VERSION 5.8 ;
BUSBITCHARS "[]" ;
DIVIDERCHAR "/" ;
UNITS
    DATABASE MICRONS 1000 ;
END UNITS

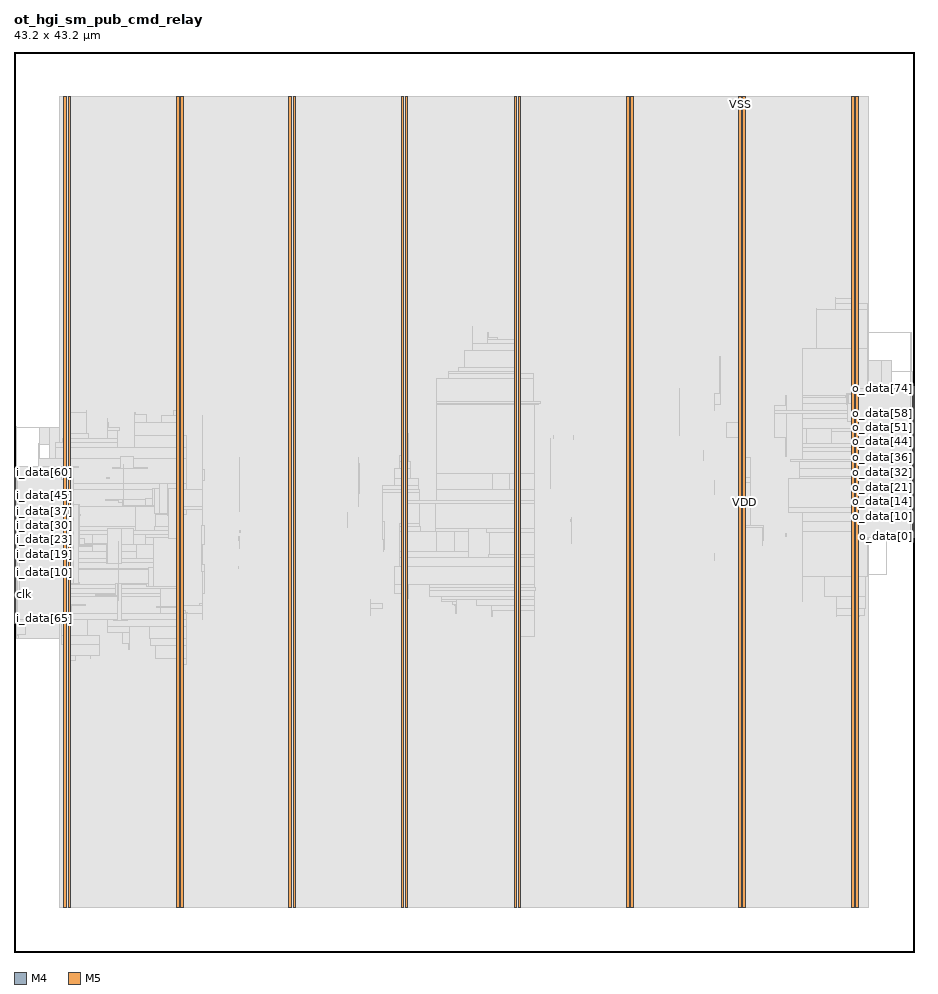
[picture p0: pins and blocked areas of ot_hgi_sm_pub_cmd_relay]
MACRO ot_hgi_sm_pub_cmd_relay
  FOREIGN ot_hgi_sm_pub_cmd_relay 0 0 ;
  CLASS BLOCK ;
  SIZE 43.2 BY 43.2 ;
  PIN clk
    DIRECTION INPUT ;
    USE SIGNAL ;
    PORT
      LAYER M4 ;
        RECT  0 17.136 0.084 17.16 ;
    END
  END clk
  PIN i_data[0]
    DIRECTION INPUT ;
    USE SIGNAL ;
    PORT
      LAYER M4 ;
        RECT  0 17.232 0.084 17.256 ;
    END
  END i_data[0]
  PIN i_data[10]
    DIRECTION INPUT ;
    USE SIGNAL ;
    PORT
      LAYER M4 ;
        RECT  0 18.192 0.084 18.216 ;
    END
  END i_data[10]
  PIN i_data[11]
    DIRECTION INPUT ;
    USE SIGNAL ;
    PORT
      LAYER M4 ;
        RECT  0 18.288 0.084 18.312 ;
    END
  END i_data[11]
  PIN i_data[12]
    DIRECTION INPUT ;
    USE SIGNAL ;
    PORT
      LAYER M4 ;
        RECT  0 18.384 0.084 18.408 ;
    END
  END i_data[12]
  PIN i_data[13]
    DIRECTION INPUT ;
    USE SIGNAL ;
    PORT
      LAYER M4 ;
        RECT  0 18.48 0.084 18.504 ;
    END
  END i_data[13]
  PIN i_data[14]
    DIRECTION INPUT ;
    USE SIGNAL ;
    PORT
      LAYER M4 ;
        RECT  0 18.576 0.084 18.6 ;
    END
  END i_data[14]
  PIN i_data[15]
    DIRECTION INPUT ;
    USE SIGNAL ;
    PORT
      LAYER M4 ;
        RECT  0 18.672 0.084 18.696 ;
    END
  END i_data[15]
  PIN i_data[16]
    DIRECTION INPUT ;
    USE SIGNAL ;
    PORT
      LAYER M4 ;
        RECT  0 18.768 0.084 18.792 ;
    END
  END i_data[16]
  PIN i_data[17]
    DIRECTION INPUT ;
    USE SIGNAL ;
    PORT
      LAYER M4 ;
        RECT  0 18.864 0.084 18.888 ;
    END
  END i_data[17]
  PIN i_data[18]
    DIRECTION INPUT ;
    USE SIGNAL ;
    PORT
      LAYER M4 ;
        RECT  0 18.96 0.084 18.984 ;
    END
  END i_data[18]
  PIN i_data[19]
    DIRECTION INPUT ;
    USE SIGNAL ;
    PORT
      LAYER M4 ;
        RECT  0 19.056 0.084 19.08 ;
    END
  END i_data[19]
  PIN i_data[1]
    DIRECTION INPUT ;
    USE SIGNAL ;
    PORT
      LAYER M4 ;
        RECT  0 17.328 0.084 17.352 ;
    END
  END i_data[1]
  PIN i_data[20]
    DIRECTION INPUT ;
    USE SIGNAL ;
    PORT
      LAYER M4 ;
        RECT  0 19.152 0.084 19.176 ;
    END
  END i_data[20]
  PIN i_data[21]
    DIRECTION INPUT ;
    USE SIGNAL ;
    PORT
      LAYER M4 ;
        RECT  0 19.248 0.084 19.272 ;
    END
  END i_data[21]
  PIN i_data[22]
    DIRECTION INPUT ;
    USE SIGNAL ;
    PORT
      LAYER M4 ;
        RECT  0 19.344 0.084 19.368 ;
    END
  END i_data[22]
  PIN i_data[23]
    DIRECTION INPUT ;
    USE SIGNAL ;
    PORT
      LAYER M4 ;
        RECT  0 19.44 0.084 19.464 ;
    END
  END i_data[23]
  PIN i_data[24]
    DIRECTION INPUT ;
    USE SIGNAL ;
    PORT
      LAYER M4 ;
        RECT  0 19.536 0.084 19.56 ;
    END
  END i_data[24]
  PIN i_data[25]
    DIRECTION INPUT ;
    USE SIGNAL ;
    PORT
      LAYER M4 ;
        RECT  0 19.632 0.084 19.656 ;
    END
  END i_data[25]
  PIN i_data[26]
    DIRECTION INPUT ;
    USE SIGNAL ;
    PORT
      LAYER M4 ;
        RECT  0 19.728 0.084 19.752 ;
    END
  END i_data[26]
  PIN i_data[27]
    DIRECTION INPUT ;
    USE SIGNAL ;
    PORT
      LAYER M4 ;
        RECT  0 19.824 0.084 19.848 ;
    END
  END i_data[27]
  PIN i_data[28]
    DIRECTION INPUT ;
    USE SIGNAL ;
    PORT
      LAYER M4 ;
        RECT  0 19.92 0.084 19.944 ;
    END
  END i_data[28]
  PIN i_data[29]
    DIRECTION INPUT ;
    USE SIGNAL ;
    PORT
      LAYER M4 ;
        RECT  0 20.016 0.084 20.04 ;
    END
  END i_data[29]
  PIN i_data[2]
    DIRECTION INPUT ;
    USE SIGNAL ;
    PORT
      LAYER M4 ;
        RECT  0 17.424 0.084 17.448 ;
    END
  END i_data[2]
  PIN i_data[30]
    DIRECTION INPUT ;
    USE SIGNAL ;
    PORT
      LAYER M4 ;
        RECT  0 20.112 0.084 20.136 ;
    END
  END i_data[30]
  PIN i_data[31]
    DIRECTION INPUT ;
    USE SIGNAL ;
    PORT
      LAYER M4 ;
        RECT  0 20.208 0.084 20.232 ;
    END
  END i_data[31]
  PIN i_data[32]
    DIRECTION INPUT ;
    USE SIGNAL ;
    PORT
      LAYER M4 ;
        RECT  0 20.304 0.084 20.328 ;
    END
  END i_data[32]
  PIN i_data[33]
    DIRECTION INPUT ;
    USE SIGNAL ;
    PORT
      LAYER M4 ;
        RECT  0 20.4 0.084 20.424 ;
    END
  END i_data[33]
  PIN i_data[34]
    DIRECTION INPUT ;
    USE SIGNAL ;
    PORT
      LAYER M4 ;
        RECT  0 20.496 0.084 20.52 ;
    END
  END i_data[34]
  PIN i_data[35]
    DIRECTION INPUT ;
    USE SIGNAL ;
    PORT
      LAYER M4 ;
        RECT  0 20.592 0.084 20.616 ;
    END
  END i_data[35]
  PIN i_data[36]
    DIRECTION INPUT ;
    USE SIGNAL ;
    PORT
      LAYER M4 ;
        RECT  0 20.688 0.084 20.712 ;
    END
  END i_data[36]
  PIN i_data[37]
    DIRECTION INPUT ;
    USE SIGNAL ;
    PORT
      LAYER M4 ;
        RECT  0 20.784 0.084 20.808 ;
    END
  END i_data[37]
  PIN i_data[38]
    DIRECTION INPUT ;
    USE SIGNAL ;
    PORT
      LAYER M4 ;
        RECT  0 20.88 0.084 20.904 ;
    END
  END i_data[38]
  PIN i_data[39]
    DIRECTION INPUT ;
    USE SIGNAL ;
    PORT
      LAYER M4 ;
        RECT  0 20.976 0.084 21 ;
    END
  END i_data[39]
  PIN i_data[3]
    DIRECTION INPUT ;
    USE SIGNAL ;
    PORT
      LAYER M4 ;
        RECT  0 17.52 0.084 17.544 ;
    END
  END i_data[3]
  PIN i_data[40]
    DIRECTION INPUT ;
    USE SIGNAL ;
    PORT
      LAYER M4 ;
        RECT  0 21.072 0.084 21.096 ;
    END
  END i_data[40]
  PIN i_data[41]
    DIRECTION INPUT ;
    USE SIGNAL ;
    PORT
      LAYER M4 ;
        RECT  0 21.168 0.084 21.192 ;
    END
  END i_data[41]
  PIN i_data[42]
    DIRECTION INPUT ;
    USE SIGNAL ;
    PORT
      LAYER M4 ;
        RECT  0 21.264 0.084 21.288 ;
    END
  END i_data[42]
  PIN i_data[43]
    DIRECTION INPUT ;
    USE SIGNAL ;
    PORT
      LAYER M4 ;
        RECT  0 21.36 0.084 21.384 ;
    END
  END i_data[43]
  PIN i_data[44]
    DIRECTION INPUT ;
    USE SIGNAL ;
    PORT
      LAYER M4 ;
        RECT  0 21.456 0.084 21.48 ;
    END
  END i_data[44]
  PIN i_data[45]
    DIRECTION INPUT ;
    USE SIGNAL ;
    PORT
      LAYER M4 ;
        RECT  0 21.552 0.084 21.576 ;
    END
  END i_data[45]
  PIN i_data[46]
    DIRECTION INPUT ;
    USE SIGNAL ;
    PORT
      LAYER M4 ;
        RECT  0 21.648 0.084 21.672 ;
    END
  END i_data[46]
  PIN i_data[47]
    DIRECTION INPUT ;
    USE SIGNAL ;
    PORT
      LAYER M4 ;
        RECT  0 21.744 0.084 21.768 ;
    END
  END i_data[47]
  PIN i_data[48]
    DIRECTION INPUT ;
    USE SIGNAL ;
    PORT
      LAYER M4 ;
        RECT  0 21.84 0.084 21.864 ;
    END
  END i_data[48]
  PIN i_data[49]
    DIRECTION INPUT ;
    USE SIGNAL ;
    PORT
      LAYER M4 ;
        RECT  0 21.936 0.084 21.96 ;
    END
  END i_data[49]
  PIN i_data[4]
    DIRECTION INPUT ;
    USE SIGNAL ;
    PORT
      LAYER M4 ;
        RECT  0 17.616 0.084 17.64 ;
    END
  END i_data[4]
  PIN i_data[50]
    DIRECTION INPUT ;
    USE SIGNAL ;
    PORT
      LAYER M4 ;
        RECT  0 22.032 0.084 22.056 ;
    END
  END i_data[50]
  PIN i_data[51]
    DIRECTION INPUT ;
    USE SIGNAL ;
    PORT
      LAYER M4 ;
        RECT  0 22.128 0.084 22.152 ;
    END
  END i_data[51]
  PIN i_data[52]
    DIRECTION INPUT ;
    USE SIGNAL ;
    PORT
      LAYER M4 ;
        RECT  0 22.224 0.084 22.248 ;
    END
  END i_data[52]
  PIN i_data[53]
    DIRECTION INPUT ;
    USE SIGNAL ;
    PORT
      LAYER M4 ;
        RECT  0 22.32 0.084 22.344 ;
    END
  END i_data[53]
  PIN i_data[54]
    DIRECTION INPUT ;
    USE SIGNAL ;
    PORT
      LAYER M4 ;
        RECT  0 22.416 0.084 22.44 ;
    END
  END i_data[54]
  PIN i_data[55]
    DIRECTION INPUT ;
    USE SIGNAL ;
    PORT
      LAYER M4 ;
        RECT  0 22.512 0.084 22.536 ;
    END
  END i_data[55]
  PIN i_data[56]
    DIRECTION INPUT ;
    USE SIGNAL ;
    PORT
      LAYER M4 ;
        RECT  0 22.608 0.084 22.632 ;
    END
  END i_data[56]
  PIN i_data[57]
    DIRECTION INPUT ;
    USE SIGNAL ;
    PORT
      LAYER M4 ;
        RECT  0 22.704 0.084 22.728 ;
    END
  END i_data[57]
  PIN i_data[58]
    DIRECTION INPUT ;
    USE SIGNAL ;
    PORT
      LAYER M4 ;
        RECT  0 22.8 0.084 22.824 ;
    END
  END i_data[58]
  PIN i_data[59]
    DIRECTION INPUT ;
    USE SIGNAL ;
    PORT
      LAYER M4 ;
        RECT  0 22.896 0.084 22.92 ;
    END
  END i_data[59]
  PIN i_data[5]
    DIRECTION INPUT ;
    USE SIGNAL ;
    PORT
      LAYER M4 ;
        RECT  0 17.712 0.084 17.736 ;
    END
  END i_data[5]
  PIN i_data[60]
    DIRECTION INPUT ;
    USE SIGNAL ;
    PORT
      LAYER M4 ;
        RECT  0 22.992 0.084 23.016 ;
    END
  END i_data[60]
  PIN i_data[61]
    DIRECTION INPUT ;
    USE SIGNAL ;
    PORT
      LAYER M4 ;
        RECT  0 23.088 0.084 23.112 ;
    END
  END i_data[61]
  PIN i_data[62]
    DIRECTION INPUT ;
    USE SIGNAL ;
    PORT
      LAYER M4 ;
        RECT  0 23.184 0.084 23.208 ;
    END
  END i_data[62]
  PIN i_data[63]
    DIRECTION INPUT ;
    USE SIGNAL ;
    PORT
      LAYER M4 ;
        RECT  0 15.792 0.084 15.816 ;
    END
  END i_data[63]
  PIN i_data[64]
    DIRECTION INPUT ;
    USE SIGNAL ;
    PORT
      LAYER M4 ;
        RECT  0 15.888 0.084 15.912 ;
    END
  END i_data[64]
  PIN i_data[65]
    DIRECTION INPUT ;
    USE SIGNAL ;
    PORT
      LAYER M4 ;
        RECT  0 15.984 0.084 16.008 ;
    END
  END i_data[65]
  PIN i_data[66]
    DIRECTION INPUT ;
    USE SIGNAL ;
    PORT
      LAYER M4 ;
        RECT  0 16.08 0.084 16.104 ;
    END
  END i_data[66]
  PIN i_data[67]
    DIRECTION INPUT ;
    USE SIGNAL ;
    PORT
      LAYER M4 ;
        RECT  0 16.176 0.084 16.2 ;
    END
  END i_data[67]
  PIN i_data[68]
    DIRECTION INPUT ;
    USE SIGNAL ;
    PORT
      LAYER M4 ;
        RECT  0 16.272 0.084 16.296 ;
    END
  END i_data[68]
  PIN i_data[69]
    DIRECTION INPUT ;
    USE SIGNAL ;
    PORT
      LAYER M4 ;
        RECT  0 16.368 0.084 16.392 ;
    END
  END i_data[69]
  PIN i_data[6]
    DIRECTION INPUT ;
    USE SIGNAL ;
    PORT
      LAYER M4 ;
        RECT  0 17.808 0.084 17.832 ;
    END
  END i_data[6]
  PIN i_data[70]
    DIRECTION INPUT ;
    USE SIGNAL ;
    PORT
      LAYER M4 ;
        RECT  0 16.464 0.084 16.488 ;
    END
  END i_data[70]
  PIN i_data[71]
    DIRECTION INPUT ;
    USE SIGNAL ;
    PORT
      LAYER M4 ;
        RECT  0 16.56 0.084 16.584 ;
    END
  END i_data[71]
  PIN i_data[72]
    DIRECTION INPUT ;
    USE SIGNAL ;
    PORT
      LAYER M4 ;
        RECT  0 16.656 0.084 16.68 ;
    END
  END i_data[72]
  PIN i_data[73]
    DIRECTION INPUT ;
    USE SIGNAL ;
    PORT
      LAYER M4 ;
        RECT  0 16.752 0.084 16.776 ;
    END
  END i_data[73]
  PIN i_data[74]
    DIRECTION INPUT ;
    USE SIGNAL ;
    PORT
      LAYER M4 ;
        RECT  0 16.848 0.084 16.872 ;
    END
  END i_data[74]
  PIN i_data[7]
    DIRECTION INPUT ;
    USE SIGNAL ;
    PORT
      LAYER M4 ;
        RECT  0 17.904 0.084 17.928 ;
    END
  END i_data[7]
  PIN i_data[8]
    DIRECTION INPUT ;
    USE SIGNAL ;
    PORT
      LAYER M4 ;
        RECT  0 18 0.084 18.024 ;
    END
  END i_data[8]
  PIN i_data[9]
    DIRECTION INPUT ;
    USE SIGNAL ;
    PORT
      LAYER M4 ;
        RECT  0 18.096 0.084 18.12 ;
    END
  END i_data[9]
  PIN i_go
    DIRECTION INPUT ;
    USE SIGNAL ;
    PORT
      LAYER M4 ;
        RECT  0 16.944 0.084 16.968 ;
    END
  END i_go
  PIN o_data[0]
    DIRECTION OUTPUT ;
    USE SIGNAL ;
    PORT
      LAYER M4 ;
        RECT  43.116 19.92 43.2 19.944 ;
    END
  END o_data[0]
  PIN o_data[10]
    DIRECTION OUTPUT ;
    USE SIGNAL ;
    PORT
      LAYER M4 ;
        RECT  43.116 20.88 43.2 20.904 ;
    END
  END o_data[10]
  PIN o_data[11]
    DIRECTION OUTPUT ;
    USE SIGNAL ;
    PORT
      LAYER M4 ;
        RECT  43.116 20.976 43.2 21 ;
    END
  END o_data[11]
  PIN o_data[12]
    DIRECTION OUTPUT ;
    USE SIGNAL ;
    PORT
      LAYER M4 ;
        RECT  43.116 21.072 43.2 21.096 ;
    END
  END o_data[12]
  PIN o_data[13]
    DIRECTION OUTPUT ;
    USE SIGNAL ;
    PORT
      LAYER M4 ;
        RECT  43.116 21.168 43.2 21.192 ;
    END
  END o_data[13]
  PIN o_data[14]
    DIRECTION OUTPUT ;
    USE SIGNAL ;
    PORT
      LAYER M4 ;
        RECT  43.116 21.264 43.2 21.288 ;
    END
  END o_data[14]
  PIN o_data[15]
    DIRECTION OUTPUT ;
    USE SIGNAL ;
    PORT
      LAYER M4 ;
        RECT  43.116 21.36 43.2 21.384 ;
    END
  END o_data[15]
  PIN o_data[16]
    DIRECTION OUTPUT ;
    USE SIGNAL ;
    PORT
      LAYER M4 ;
        RECT  43.116 21.456 43.2 21.48 ;
    END
  END o_data[16]
  PIN o_data[17]
    DIRECTION OUTPUT ;
    USE SIGNAL ;
    PORT
      LAYER M4 ;
        RECT  43.116 21.552 43.2 21.576 ;
    END
  END o_data[17]
  PIN o_data[18]
    DIRECTION OUTPUT ;
    USE SIGNAL ;
    PORT
      LAYER M4 ;
        RECT  43.116 21.648 43.2 21.672 ;
    END
  END o_data[18]
  PIN o_data[19]
    DIRECTION OUTPUT ;
    USE SIGNAL ;
    PORT
      LAYER M4 ;
        RECT  43.116 21.744 43.2 21.768 ;
    END
  END o_data[19]
  PIN o_data[1]
    DIRECTION OUTPUT ;
    USE SIGNAL ;
    PORT
      LAYER M4 ;
        RECT  43.116 20.016 43.2 20.04 ;
    END
  END o_data[1]
  PIN o_data[20]
    DIRECTION OUTPUT ;
    USE SIGNAL ;
    PORT
      LAYER M4 ;
        RECT  43.116 21.84 43.2 21.864 ;
    END
  END o_data[20]
  PIN o_data[21]
    DIRECTION OUTPUT ;
    USE SIGNAL ;
    PORT
      LAYER M4 ;
        RECT  43.116 21.936 43.2 21.96 ;
    END
  END o_data[21]
  PIN o_data[22]
    DIRECTION OUTPUT ;
    USE SIGNAL ;
    PORT
      LAYER M4 ;
        RECT  43.116 22.032 43.2 22.056 ;
    END
  END o_data[22]
  PIN o_data[23]
    DIRECTION OUTPUT ;
    USE SIGNAL ;
    PORT
      LAYER M4 ;
        RECT  43.116 22.128 43.2 22.152 ;
    END
  END o_data[23]
  PIN o_data[24]
    DIRECTION OUTPUT ;
    USE SIGNAL ;
    PORT
      LAYER M4 ;
        RECT  43.116 22.224 43.2 22.248 ;
    END
  END o_data[24]
  PIN o_data[25]
    DIRECTION OUTPUT ;
    USE SIGNAL ;
    PORT
      LAYER M4 ;
        RECT  43.116 22.32 43.2 22.344 ;
    END
  END o_data[25]
  PIN o_data[26]
    DIRECTION OUTPUT ;
    USE SIGNAL ;
    PORT
      LAYER M4 ;
        RECT  43.116 22.416 43.2 22.44 ;
    END
  END o_data[26]
  PIN o_data[27]
    DIRECTION OUTPUT ;
    USE SIGNAL ;
    PORT
      LAYER M4 ;
        RECT  43.116 22.512 43.2 22.536 ;
    END
  END o_data[27]
  PIN o_data[28]
    DIRECTION OUTPUT ;
    USE SIGNAL ;
    PORT
      LAYER M4 ;
        RECT  43.116 22.608 43.2 22.632 ;
    END
  END o_data[28]
  PIN o_data[29]
    DIRECTION OUTPUT ;
    USE SIGNAL ;
    PORT
      LAYER M4 ;
        RECT  43.116 22.704 43.2 22.728 ;
    END
  END o_data[29]
  PIN o_data[2]
    DIRECTION OUTPUT ;
    USE SIGNAL ;
    PORT
      LAYER M4 ;
        RECT  43.116 20.112 43.2 20.136 ;
    END
  END o_data[2]
  PIN o_data[30]
    DIRECTION OUTPUT ;
    USE SIGNAL ;
    PORT
      LAYER M4 ;
        RECT  43.116 22.8 43.2 22.824 ;
    END
  END o_data[30]
  PIN o_data[31]
    DIRECTION OUTPUT ;
    USE SIGNAL ;
    PORT
      LAYER M4 ;
        RECT  43.116 22.896 43.2 22.92 ;
    END
  END o_data[31]
  PIN o_data[32]
    DIRECTION OUTPUT ;
    USE SIGNAL ;
    PORT
      LAYER M4 ;
        RECT  43.116 22.992 43.2 23.016 ;
    END
  END o_data[32]
  PIN o_data[33]
    DIRECTION OUTPUT ;
    USE SIGNAL ;
    PORT
      LAYER M4 ;
        RECT  43.116 23.088 43.2 23.112 ;
    END
  END o_data[33]
  PIN o_data[34]
    DIRECTION OUTPUT ;
    USE SIGNAL ;
    PORT
      LAYER M4 ;
        RECT  43.116 23.184 43.2 23.208 ;
    END
  END o_data[34]
  PIN o_data[35]
    DIRECTION OUTPUT ;
    USE SIGNAL ;
    PORT
      LAYER M4 ;
        RECT  43.116 23.28 43.2 23.304 ;
    END
  END o_data[35]
  PIN o_data[36]
    DIRECTION OUTPUT ;
    USE SIGNAL ;
    PORT
      LAYER M4 ;
        RECT  43.116 23.376 43.2 23.4 ;
    END
  END o_data[36]
  PIN o_data[37]
    DIRECTION OUTPUT ;
    USE SIGNAL ;
    PORT
      LAYER M4 ;
        RECT  43.116 23.472 43.2 23.496 ;
    END
  END o_data[37]
  PIN o_data[38]
    DIRECTION OUTPUT ;
    USE SIGNAL ;
    PORT
      LAYER M4 ;
        RECT  43.116 23.568 43.2 23.592 ;
    END
  END o_data[38]
  PIN o_data[39]
    DIRECTION OUTPUT ;
    USE SIGNAL ;
    PORT
      LAYER M4 ;
        RECT  43.116 23.664 43.2 23.688 ;
    END
  END o_data[39]
  PIN o_data[3]
    DIRECTION OUTPUT ;
    USE SIGNAL ;
    PORT
      LAYER M4 ;
        RECT  43.116 20.208 43.2 20.232 ;
    END
  END o_data[3]
  PIN o_data[40]
    DIRECTION OUTPUT ;
    USE SIGNAL ;
    PORT
      LAYER M4 ;
        RECT  43.116 23.76 43.2 23.784 ;
    END
  END o_data[40]
  PIN o_data[41]
    DIRECTION OUTPUT ;
    USE SIGNAL ;
    PORT
      LAYER M4 ;
        RECT  43.116 23.856 43.2 23.88 ;
    END
  END o_data[41]
  PIN o_data[42]
    DIRECTION OUTPUT ;
    USE SIGNAL ;
    PORT
      LAYER M4 ;
        RECT  43.116 23.952 43.2 23.976 ;
    END
  END o_data[42]
  PIN o_data[43]
    DIRECTION OUTPUT ;
    USE SIGNAL ;
    PORT
      LAYER M4 ;
        RECT  43.116 24.048 43.2 24.072 ;
    END
  END o_data[43]
  PIN o_data[44]
    DIRECTION OUTPUT ;
    USE SIGNAL ;
    PORT
      LAYER M4 ;
        RECT  43.116 24.144 43.2 24.168 ;
    END
  END o_data[44]
  PIN o_data[45]
    DIRECTION OUTPUT ;
    USE SIGNAL ;
    PORT
      LAYER M4 ;
        RECT  43.116 24.24 43.2 24.264 ;
    END
  END o_data[45]
  PIN o_data[46]
    DIRECTION OUTPUT ;
    USE SIGNAL ;
    PORT
      LAYER M4 ;
        RECT  43.116 24.336 43.2 24.36 ;
    END
  END o_data[46]
  PIN o_data[47]
    DIRECTION OUTPUT ;
    USE SIGNAL ;
    PORT
      LAYER M4 ;
        RECT  43.116 24.432 43.2 24.456 ;
    END
  END o_data[47]
  PIN o_data[48]
    DIRECTION OUTPUT ;
    USE SIGNAL ;
    PORT
      LAYER M4 ;
        RECT  43.116 24.528 43.2 24.552 ;
    END
  END o_data[48]
  PIN o_data[49]
    DIRECTION OUTPUT ;
    USE SIGNAL ;
    PORT
      LAYER M4 ;
        RECT  43.116 24.624 43.2 24.648 ;
    END
  END o_data[49]
  PIN o_data[4]
    DIRECTION OUTPUT ;
    USE SIGNAL ;
    PORT
      LAYER M4 ;
        RECT  43.116 20.304 43.2 20.328 ;
    END
  END o_data[4]
  PIN o_data[50]
    DIRECTION OUTPUT ;
    USE SIGNAL ;
    PORT
      LAYER M4 ;
        RECT  43.116 24.72 43.2 24.744 ;
    END
  END o_data[50]
  PIN o_data[51]
    DIRECTION OUTPUT ;
    USE SIGNAL ;
    PORT
      LAYER M4 ;
        RECT  43.116 24.816 43.2 24.84 ;
    END
  END o_data[51]
  PIN o_data[52]
    DIRECTION OUTPUT ;
    USE SIGNAL ;
    PORT
      LAYER M4 ;
        RECT  43.116 24.912 43.2 24.936 ;
    END
  END o_data[52]
  PIN o_data[53]
    DIRECTION OUTPUT ;
    USE SIGNAL ;
    PORT
      LAYER M4 ;
        RECT  43.116 25.008 43.2 25.032 ;
    END
  END o_data[53]
  PIN o_data[54]
    DIRECTION OUTPUT ;
    USE SIGNAL ;
    PORT
      LAYER M4 ;
        RECT  43.116 25.104 43.2 25.128 ;
    END
  END o_data[54]
  PIN o_data[55]
    DIRECTION OUTPUT ;
    USE SIGNAL ;
    PORT
      LAYER M4 ;
        RECT  43.116 25.2 43.2 25.224 ;
    END
  END o_data[55]
  PIN o_data[56]
    DIRECTION OUTPUT ;
    USE SIGNAL ;
    PORT
      LAYER M4 ;
        RECT  43.116 25.296 43.2 25.32 ;
    END
  END o_data[56]
  PIN o_data[57]
    DIRECTION OUTPUT ;
    USE SIGNAL ;
    PORT
      LAYER M4 ;
        RECT  43.116 25.392 43.2 25.416 ;
    END
  END o_data[57]
  PIN o_data[58]
    DIRECTION OUTPUT ;
    USE SIGNAL ;
    PORT
      LAYER M4 ;
        RECT  43.116 25.488 43.2 25.512 ;
    END
  END o_data[58]
  PIN o_data[59]
    DIRECTION OUTPUT ;
    USE SIGNAL ;
    PORT
      LAYER M4 ;
        RECT  43.116 25.584 43.2 25.608 ;
    END
  END o_data[59]
  PIN o_data[5]
    DIRECTION OUTPUT ;
    USE SIGNAL ;
    PORT
      LAYER M4 ;
        RECT  43.116 20.4 43.2 20.424 ;
    END
  END o_data[5]
  PIN o_data[60]
    DIRECTION OUTPUT ;
    USE SIGNAL ;
    PORT
      LAYER M4 ;
        RECT  43.116 25.68 43.2 25.704 ;
    END
  END o_data[60]
  PIN o_data[61]
    DIRECTION OUTPUT ;
    USE SIGNAL ;
    PORT
      LAYER M4 ;
        RECT  43.116 25.776 43.2 25.8 ;
    END
  END o_data[61]
  PIN o_data[62]
    DIRECTION OUTPUT ;
    USE SIGNAL ;
    PORT
      LAYER M4 ;
        RECT  43.116 25.872 43.2 25.896 ;
    END
  END o_data[62]
  PIN o_data[63]
    DIRECTION OUTPUT ;
    USE SIGNAL ;
    PORT
      LAYER M4 ;
        RECT  43.116 25.968 43.2 25.992 ;
    END
  END o_data[63]
  PIN o_data[64]
    DIRECTION OUTPUT ;
    USE SIGNAL ;
    PORT
      LAYER M4 ;
        RECT  43.116 26.064 43.2 26.088 ;
    END
  END o_data[64]
  PIN o_data[65]
    DIRECTION OUTPUT ;
    USE SIGNAL ;
    PORT
      LAYER M4 ;
        RECT  43.116 26.16 43.2 26.184 ;
    END
  END o_data[65]
  PIN o_data[66]
    DIRECTION OUTPUT ;
    USE SIGNAL ;
    PORT
      LAYER M4 ;
        RECT  43.116 26.256 43.2 26.28 ;
    END
  END o_data[66]
  PIN o_data[67]
    DIRECTION OUTPUT ;
    USE SIGNAL ;
    PORT
      LAYER M4 ;
        RECT  43.116 26.352 43.2 26.376 ;
    END
  END o_data[67]
  PIN o_data[68]
    DIRECTION OUTPUT ;
    USE SIGNAL ;
    PORT
      LAYER M4 ;
        RECT  43.116 26.448 43.2 26.472 ;
    END
  END o_data[68]
  PIN o_data[69]
    DIRECTION OUTPUT ;
    USE SIGNAL ;
    PORT
      LAYER M4 ;
        RECT  43.116 26.544 43.2 26.568 ;
    END
  END o_data[69]
  PIN o_data[6]
    DIRECTION OUTPUT ;
    USE SIGNAL ;
    PORT
      LAYER M4 ;
        RECT  43.116 20.496 43.2 20.52 ;
    END
  END o_data[6]
  PIN o_data[70]
    DIRECTION OUTPUT ;
    USE SIGNAL ;
    PORT
      LAYER M4 ;
        RECT  43.116 26.64 43.2 26.664 ;
    END
  END o_data[70]
  PIN o_data[71]
    DIRECTION OUTPUT ;
    USE SIGNAL ;
    PORT
      LAYER M4 ;
        RECT  43.116 26.736 43.2 26.76 ;
    END
  END o_data[71]
  PIN o_data[72]
    DIRECTION OUTPUT ;
    USE SIGNAL ;
    PORT
      LAYER M4 ;
        RECT  43.116 26.832 43.2 26.856 ;
    END
  END o_data[72]
  PIN o_data[73]
    DIRECTION OUTPUT ;
    USE SIGNAL ;
    PORT
      LAYER M4 ;
        RECT  43.116 26.928 43.2 26.952 ;
    END
  END o_data[73]
  PIN o_data[74]
    DIRECTION OUTPUT ;
    USE SIGNAL ;
    PORT
      LAYER M4 ;
        RECT  43.116 27.024 43.2 27.048 ;
    END
  END o_data[74]
  PIN o_data[7]
    DIRECTION OUTPUT ;
    USE SIGNAL ;
    PORT
      LAYER M4 ;
        RECT  43.116 20.592 43.2 20.616 ;
    END
  END o_data[7]
  PIN o_data[8]
    DIRECTION OUTPUT ;
    USE SIGNAL ;
    PORT
      LAYER M4 ;
        RECT  43.116 20.688 43.2 20.712 ;
    END
  END o_data[8]
  PIN o_data[9]
    DIRECTION OUTPUT ;
    USE SIGNAL ;
    PORT
      LAYER M4 ;
        RECT  43.116 20.784 43.2 20.808 ;
    END
  END o_data[9]
  PIN o_go
    DIRECTION OUTPUT ;
    USE SIGNAL ;
    PORT
      LAYER M4 ;
        RECT  43.116 27.12 43.2 27.144 ;
    END
  END o_go
  PIN rn
    DIRECTION INPUT ;
    USE SIGNAL ;
    PORT
      LAYER M4 ;
        RECT  0 17.04 0.084 17.064 ;
    END
  END rn
  PIN VDD
    DIRECTION INOUT ;
    USE POWER ;
    PORT
      LAYER M5 ;
        RECT  40.392 2.151 40.512 41.049 ;
        RECT  34.992 2.151 35.112 41.049 ;
        RECT  29.592 2.151 29.712 41.049 ;
        RECT  24.192 2.151 24.312 41.049 ;
        RECT  18.792 2.151 18.912 41.049 ;
        RECT  13.392 2.151 13.512 41.049 ;
        RECT  7.992 2.151 8.112 41.049 ;
        RECT  2.592 2.151 2.712 41.049 ;
    END
  END VDD
  PIN VSS
    DIRECTION INOUT ;
    USE GROUND ;
    PORT
      LAYER M5 ;
        RECT  40.2 2.137 40.32 41.063 ;
        RECT  34.8 2.137 34.92 41.063 ;
        RECT  29.4 2.137 29.52 41.063 ;
        RECT  24 2.137 24.12 41.063 ;
        RECT  18.6 2.137 18.72 41.063 ;
        RECT  13.2 2.137 13.32 41.063 ;
        RECT  7.8 2.137 7.92 41.063 ;
        RECT  2.4 2.137 2.52 41.063 ;
    END
  END VSS
  # OT_OBS_CLOSED layer=M5 d_um=1.536 added=0
  OBS
    LAYER RVTN ;
     RECT  2.16 2.16 41.04 2.295 ;
     RECT  2.16 2.565 41.04 2.835 ;
     RECT  2.16 3.105 41.04 3.375 ;
     RECT  2.16 3.645 41.04 3.915 ;
     RECT  2.16 4.185 41.04 4.455 ;
     RECT  2.16 4.725 41.04 4.995 ;
     RECT  2.16 5.265 41.04 5.535 ;
     RECT  2.16 5.805 41.04 6.075 ;
     RECT  2.16 6.345 41.04 6.615 ;
     RECT  2.16 6.885 41.04 7.155 ;
     RECT  2.16 7.425 41.04 7.695 ;
     RECT  2.16 7.965 41.04 8.235 ;
     RECT  2.16 8.505 41.04 8.775 ;
     RECT  2.16 9.045 41.04 9.315 ;
     RECT  2.16 9.585 41.04 9.855 ;
     RECT  2.16 10.125 41.04 10.395 ;
     RECT  2.16 10.665 41.04 10.935 ;
     RECT  2.16 11.205 41.04 11.475 ;
     RECT  2.16 11.745 41.04 12.015 ;
     RECT  2.16 12.285 41.04 12.555 ;
     RECT  2.16 12.825 41.04 13.095 ;
     RECT  2.16 13.365 41.04 13.635 ;
     RECT  2.16 13.905 41.04 14.175 ;
     RECT  2.16 14.445 41.04 14.715 ;
     RECT  2.16 14.985 41.04 15.255 ;
     RECT  2.16 15.525 41.04 15.795 ;
     RECT  2.16 16.065 41.04 16.335 ;
     RECT  2.16 16.605 41.04 16.875 ;
     RECT  2.16 17.145 41.04 17.415 ;
     RECT  2.16 17.685 41.04 17.955 ;
     RECT  2.16 18.225 41.04 18.495 ;
     RECT  2.16 18.765 41.04 19.035 ;
     RECT  2.16 19.305 41.04 19.575 ;
     RECT  2.16 19.845 41.04 20.115 ;
     RECT  2.16 20.385 41.04 20.655 ;
     RECT  2.16 20.925 41.04 21.195 ;
     RECT  2.16 21.465 41.04 21.735 ;
     RECT  2.16 22.005 41.04 22.275 ;
     RECT  2.16 22.545 41.04 22.815 ;
     RECT  2.16 23.085 41.04 23.355 ;
     RECT  2.16 23.625 41.04 23.895 ;
     RECT  2.16 24.165 41.04 24.435 ;
     RECT  2.16 24.705 41.04 24.975 ;
     RECT  2.16 25.245 41.04 25.515 ;
     RECT  2.16 25.785 41.04 26.055 ;
     RECT  2.16 26.325 41.04 26.595 ;
     RECT  2.16 26.865 41.04 27.135 ;
     RECT  2.16 27.405 41.04 27.675 ;
     RECT  2.16 27.945 41.04 28.215 ;
     RECT  2.16 28.485 41.04 28.755 ;
     RECT  2.16 29.025 41.04 29.295 ;
     RECT  2.16 29.565 41.04 29.835 ;
     RECT  2.16 30.105 41.04 30.375 ;
     RECT  2.16 30.645 41.04 30.915 ;
     RECT  2.16 31.185 41.04 31.455 ;
     RECT  2.16 31.725 41.04 31.995 ;
     RECT  2.16 32.265 41.04 32.535 ;
     RECT  2.16 32.805 41.04 33.075 ;
     RECT  2.16 33.345 41.04 33.615 ;
     RECT  2.16 33.885 41.04 34.155 ;
     RECT  2.16 34.425 41.04 34.695 ;
     RECT  2.16 34.965 41.04 35.235 ;
     RECT  2.16 35.505 41.04 35.775 ;
     RECT  2.16 36.045 41.04 36.315 ;
     RECT  2.16 36.585 41.04 36.855 ;
     RECT  2.16 37.125 41.04 37.395 ;
     RECT  2.16 37.665 41.04 37.935 ;
     RECT  2.16 38.205 41.04 38.475 ;
     RECT  2.16 38.745 41.04 39.015 ;
     RECT  2.16 39.285 41.04 39.555 ;
     RECT  2.16 39.825 41.04 40.095 ;
     RECT  2.16 40.365 41.04 40.635 ;
     RECT  2.16 40.905 41.04 41.04 ;
    LAYER RVTP ;
     RECT  2.16 2.295 41.04 2.565 ;
     RECT  2.16 2.835 41.04 3.105 ;
     RECT  2.16 3.375 41.04 3.645 ;
     RECT  2.16 3.915 41.04 4.185 ;
     RECT  2.16 4.455 41.04 4.725 ;
     RECT  2.16 4.995 41.04 5.265 ;
     RECT  2.16 5.535 41.04 5.805 ;
     RECT  2.16 6.075 41.04 6.345 ;
     RECT  2.16 6.615 41.04 6.885 ;
     RECT  2.16 7.155 41.04 7.425 ;
     RECT  2.16 7.695 41.04 7.965 ;
     RECT  2.16 8.235 41.04 8.505 ;
     RECT  2.16 8.775 41.04 9.045 ;
     RECT  2.16 9.315 41.04 9.585 ;
     RECT  2.16 9.855 41.04 10.125 ;
     RECT  2.16 10.395 41.04 10.665 ;
     RECT  2.16 10.935 41.04 11.205 ;
     RECT  2.16 11.475 41.04 11.745 ;
     RECT  2.16 12.015 41.04 12.285 ;
     RECT  2.16 12.555 41.04 12.825 ;
     RECT  2.16 13.095 41.04 13.365 ;
     RECT  2.16 13.635 41.04 13.905 ;
     RECT  2.16 14.175 41.04 14.445 ;
     RECT  2.16 14.715 41.04 14.985 ;
     RECT  2.16 15.255 41.04 15.525 ;
     RECT  2.16 15.795 41.04 16.065 ;
     RECT  2.16 16.335 41.04 16.605 ;
     RECT  2.16 16.875 41.04 17.145 ;
     RECT  2.16 17.415 41.04 17.685 ;
     RECT  2.16 17.955 41.04 18.225 ;
     RECT  2.16 18.495 41.04 18.765 ;
     RECT  2.16 19.035 41.04 19.305 ;
     RECT  2.16 19.575 41.04 19.845 ;
     RECT  2.16 20.115 41.04 20.385 ;
     RECT  2.16 20.655 41.04 20.925 ;
     RECT  2.16 21.195 41.04 21.465 ;
     RECT  2.16 21.735 41.04 22.005 ;
     RECT  2.16 22.275 41.04 22.545 ;
     RECT  2.16 22.815 41.04 23.085 ;
     RECT  2.16 23.355 41.04 23.625 ;
     RECT  2.16 23.895 41.04 24.165 ;
     RECT  2.16 24.435 41.04 24.705 ;
     RECT  2.16 24.975 41.04 25.245 ;
     RECT  2.16 25.515 41.04 25.785 ;
     RECT  2.16 26.055 41.04 26.325 ;
     RECT  2.16 26.595 41.04 26.865 ;
     RECT  2.16 27.135 41.04 27.405 ;
     RECT  2.16 27.675 41.04 27.945 ;
     RECT  2.16 28.215 41.04 28.485 ;
     RECT  2.16 28.755 41.04 29.025 ;
     RECT  2.16 29.295 41.04 29.565 ;
     RECT  2.16 29.835 41.04 30.105 ;
     RECT  2.16 30.375 41.04 30.645 ;
     RECT  2.16 30.915 41.04 31.185 ;
     RECT  2.16 31.455 41.04 31.725 ;
     RECT  2.16 31.995 41.04 32.265 ;
     RECT  2.16 32.535 41.04 32.805 ;
     RECT  2.16 33.075 41.04 33.345 ;
     RECT  2.16 33.615 41.04 33.885 ;
     RECT  2.16 34.155 41.04 34.425 ;
     RECT  2.16 34.695 41.04 34.965 ;
     RECT  2.16 35.235 41.04 35.505 ;
     RECT  2.16 35.775 41.04 36.045 ;
     RECT  2.16 36.315 41.04 36.585 ;
     RECT  2.16 36.855 41.04 37.125 ;
     RECT  2.16 37.395 41.04 37.665 ;
     RECT  2.16 37.935 41.04 38.205 ;
     RECT  2.16 38.475 41.04 38.745 ;
     RECT  2.16 39.015 41.04 39.285 ;
     RECT  2.16 39.555 41.04 39.825 ;
     RECT  2.16 40.095 41.04 40.365 ;
     RECT  2.16 40.635 41.04 40.905 ;
    LAYER M1 ;
     RECT  2.16 2.151 41.04 41.049 ;
    LAYER M2 ;
     RECT  0.103 15.03 0.139 15.048 ;
     RECT  0.103 16.38 0.139 16.398 ;
     RECT  0.103 19.818 0.139 20.34 ;
     RECT  0.139 16.272 0.175 16.668 ;
     RECT  0.103 17.658 0.175 18.216 ;
     RECT  0.139 19.35 0.203 20.34 ;
     RECT  0.139 15.03 0.211 15.318 ;
     RECT  0.175 16.272 0.211 18.216 ;
     RECT  0.203 19.35 0.347 20.214 ;
     RECT  0.347 19.35 0.383 19.836 ;
     RECT  1.183 24.372 1.219 24.39 ;
     RECT  0.103 25.182 1.219 25.2 ;
     RECT  1.219 24.372 1.687 25.2 ;
     RECT  1.147 22.482 1.723 22.5 ;
     RECT  1.687 23.67 1.723 25.2 ;
     RECT  0.211 15.03 2.16 18.216 ;
     RECT  0.383 19.35 2.16 19.368 ;
     RECT  1.723 22.482 2.16 25.2 ;
     RECT  2.16 2.151 41.04 41.049 ;
     RECT  41.04 19.926 41.639 28.404 ;
     RECT  41.04 18.126 41.891 18.144 ;
     RECT  41.639 25.956 42.107 28.404 ;
     RECT  41.639 19.926 42.143 25.164 ;
     RECT  42.107 27.846 42.143 28.404 ;
     RECT  42.143 20.124 42.179 25.002 ;
     RECT  42.107 25.956 42.179 27.054 ;
     RECT  42.179 21.402 42.215 21.762 ;
     RECT  42.179 24.246 42.215 25.002 ;
     RECT  42.179 26.406 42.215 26.622 ;
     RECT  42.215 24.246 42.251 24.696 ;
     RECT  42.215 21.402 43.079 21.654 ;
     RECT  41.04 29.736 43.079 29.754 ;
     RECT  43.079 21.402 43.115 21.42 ;
     RECT  42.179 22.716 43.115 23.346 ;
     RECT  42.251 24.246 43.115 24.264 ;
     RECT  42.215 26.406 43.115 26.424 ;
     RECT  42.143 27.846 43.115 27.864 ;
    LAYER M3 ;
     RECT  2.415 2.143 2.505 2.413 ;
     RECT  7.815 2.143 7.905 2.413 ;
     RECT  13.215 2.143 13.305 2.413 ;
     RECT  18.615 2.143 18.705 2.413 ;
     RECT  24.015 2.143 24.105 2.413 ;
     RECT  29.415 2.143 29.505 2.413 ;
     RECT  34.815 2.143 34.905 2.413 ;
     RECT  40.215 2.143 40.305 2.413 ;
     RECT  7.815 2.413 8.097 13.801 ;
     RECT  2.415 2.413 2.697 13.981 ;
     RECT  7.815 13.801 8.262 14.107 ;
     RECT  3.672 14.071 3.69 14.215 ;
     RECT  2.415 13.981 2.934 14.251 ;
     RECT  3.672 14.215 4.086 14.251 ;
     RECT  6.804 14.107 8.262 14.719 ;
     RECT  2.415 14.251 4.086 14.755 ;
     RECT  5.508 14.521 5.526 14.791 ;
     RECT  6.552 14.719 8.262 15.061 ;
     RECT  24.015 2.413 24.297 15.151 ;
     RECT  2.304 14.755 4.086 15.179 ;
     RECT  0.108 15.025 0.126 15.187 ;
     RECT  0.108 15.187 0.198 15.259 ;
     RECT  5.184 14.791 5.526 15.331 ;
     RECT  4.464 15.331 5.526 15.601 ;
     RECT  6.516 15.061 8.262 15.601 ;
     RECT  2.304 15.179 3.546 15.961 ;
     RECT  4.464 15.601 8.262 15.961 ;
     RECT  40.215 2.413 40.497 16.105 ;
     RECT  39.456 16.105 39.474 16.141 ;
     RECT  40.215 16.105 40.59 16.141 ;
     RECT  2.304 15.961 8.262 16.259 ;
     RECT  7.776 16.259 8.262 16.261 ;
     RECT  9.036 15.961 9.054 16.261 ;
     RECT  22.932 16.105 22.95 16.411 ;
     RECT  24.015 15.151 25.002 16.411 ;
     RECT  17.1 16.141 17.118 16.501 ;
     RECT  39.456 16.141 40.842 16.501 ;
     RECT  21.204 16.267 21.222 16.609 ;
     RECT  7.776 16.261 9.054 16.637 ;
     RECT  22.932 16.411 25.002 16.645 ;
     RECT  0.108 15.259 0.558 16.651 ;
     RECT  21.132 16.609 21.222 16.681 ;
     RECT  8.892 16.637 9.054 16.709 ;
     RECT  17.1 16.501 17.694 16.709 ;
     RECT  0.108 16.651 0.63 16.781 ;
     RECT  21.024 16.681 21.222 16.843 ;
     RECT  20.52 16.843 21.222 16.915 ;
     RECT  22.212 16.645 25.002 16.915 ;
     RECT  17.1 16.709 17.118 16.943 ;
     RECT  18.615 2.413 18.897 16.951 ;
     RECT  2.304 16.259 7.038 17.077 ;
     RECT  20.52 16.915 25.002 17.077 ;
     RECT  39.456 16.501 40.878 17.077 ;
     RECT  2.232 17.077 7.038 17.213 ;
     RECT  9.036 16.709 9.054 17.221 ;
     RECT  18.615 16.951 18.954 17.221 ;
     RECT  0.108 16.781 0.558 17.261 ;
     RECT  19.944 17.077 25.002 17.347 ;
     RECT  2.304 17.213 7.038 17.455 ;
     RECT  7.776 16.637 8.097 17.455 ;
     RECT  19.944 17.347 25.038 17.483 ;
     RECT  18.252 17.221 18.954 17.617 ;
     RECT  19.944 17.483 25.002 17.617 ;
     RECT  2.304 17.455 8.097 17.645 ;
     RECT  0.108 17.261 0.522 18.031 ;
     RECT  37.836 16.807 37.854 18.031 ;
     RECT  38.88 17.077 40.878 18.031 ;
     RECT  9.036 17.221 9.126 18.265 ;
     RECT  2.376 17.645 8.097 18.379 ;
     RECT  2.304 18.379 8.097 18.427 ;
     RECT  10.764 18.391 10.782 18.491 ;
     RECT  18.252 17.617 25.002 18.527 ;
     RECT  9 18.265 9.126 18.599 ;
     RECT  0.108 18.031 0.558 18.605 ;
     RECT  2.304 18.427 8.154 18.689 ;
     RECT  2.304 18.689 8.097 18.869 ;
     RECT  18.504 18.527 25.002 18.959 ;
     RECT  0.18 18.605 0.558 19.085 ;
     RECT  22.788 18.959 25.002 19.103 ;
     RECT  34.815 2.413 35.097 19.111 ;
     RECT  33.624 18.769 33.642 19.139 ;
     RECT  2.304 18.869 5.886 19.229 ;
     RECT  18.504 18.959 21.834 19.229 ;
     RECT  34.776 19.111 35.097 19.229 ;
     RECT  17.712 19.237 17.73 19.309 ;
     RECT  0.18 19.085 0.342 19.345 ;
     RECT  2.304 19.229 3.762 19.483 ;
     RECT  2.232 19.483 3.762 19.535 ;
     RECT  9 18.599 9.054 19.543 ;
     RECT  4.536 19.229 5.886 19.675 ;
     RECT  6.696 18.869 8.097 19.675 ;
     RECT  10.8 19.381 10.818 19.741 ;
     RECT  35.928 19.507 35.946 19.741 ;
     RECT  17.712 19.309 17.766 19.777 ;
     RECT  0.144 19.345 0.342 19.813 ;
     RECT  41.868 18.121 41.886 19.921 ;
     RECT  0.108 19.813 0.378 19.949 ;
     RECT  10.764 19.741 10.818 19.949 ;
     RECT  2.304 19.535 3.762 20.047 ;
     RECT  4.536 19.675 8.097 20.047 ;
     RECT  37.044 19.921 37.062 20.111 ;
     RECT  41.868 19.921 42.138 20.119 ;
     RECT  22.824 19.103 25.002 20.155 ;
     RECT  18.504 19.229 20.286 20.183 ;
     RECT  20.232 20.183 20.286 20.191 ;
     RECT  21.132 19.229 21.834 20.191 ;
     RECT  37.836 18.031 40.95 20.191 ;
     RECT  2.304 20.047 8.097 20.219 ;
     RECT  10.836 20.119 10.854 20.219 ;
     RECT  20.232 20.191 21.834 20.317 ;
     RECT  22.68 20.155 25.002 20.317 ;
     RECT  0.108 19.949 0.342 20.333 ;
     RECT  0.108 20.333 0.198 20.345 ;
     RECT  34.815 19.229 35.097 20.353 ;
     RECT  35.928 19.741 35.982 20.353 ;
     RECT  6.732 20.219 8.097 20.417 ;
     RECT  18.504 20.183 19.494 20.417 ;
     RECT  1.152 20.395 1.278 20.443 ;
     RECT  2.304 20.219 5.814 20.443 ;
     RECT  9 19.543 9.126 20.453 ;
     RECT  0.18 20.345 0.198 20.477 ;
     RECT  9.036 20.453 9.126 20.489 ;
     RECT  34.815 20.353 35.982 20.489 ;
     RECT  18.504 20.417 19.458 20.579 ;
     RECT  17.676 19.777 17.766 20.651 ;
     RECT  26.748 19.615 26.766 20.659 ;
     RECT  37.836 20.191 41.094 20.659 ;
     RECT  41.868 20.119 42.174 20.659 ;
     RECT  26.712 20.659 26.766 20.759 ;
     RECT  26.748 20.759 26.766 20.849 ;
     RECT  6.768 20.417 8.097 21.001 ;
     RECT  37.836 20.659 42.174 21.091 ;
     RECT  15.984 20.389 16.002 21.119 ;
     RECT  6.768 21.001 8.298 21.235 ;
     RECT  9.036 20.489 9.054 21.235 ;
     RECT  37.188 21.091 42.174 21.355 ;
     RECT  1.152 20.443 5.814 21.397 ;
     RECT  6.768 21.235 9.054 21.397 ;
     RECT  0.324 21.355 0.342 21.485 ;
     RECT  18.615 20.579 19.458 21.505 ;
     RECT  20.232 20.317 25.002 21.505 ;
     RECT  34.815 20.489 35.37 21.541 ;
     RECT  43.092 21.397 43.11 21.631 ;
     RECT  18.615 21.505 25.002 21.659 ;
     RECT  34.776 21.541 35.37 21.659 ;
     RECT  43.056 21.631 43.11 21.677 ;
     RECT  43.056 21.677 43.074 21.965 ;
     RECT  16.524 21.397 16.542 22.009 ;
     RECT  17.676 20.651 17.694 22.045 ;
     RECT  18.615 21.659 19.458 22.045 ;
     RECT  1.152 21.397 9.054 22.199 ;
     RECT  17.676 22.045 19.458 22.199 ;
     RECT  20.268 21.659 25.002 22.199 ;
     RECT  17.676 22.199 19.422 22.379 ;
     RECT  1.152 22.199 8.298 22.505 ;
     RECT  34.815 21.659 35.37 22.549 ;
     RECT  9.036 22.199 9.054 22.621 ;
     RECT  33.624 21.937 33.642 22.649 ;
     RECT  18.252 22.379 19.422 22.739 ;
     RECT  37.188 21.355 42.21 22.739 ;
     RECT  34.776 22.549 35.37 22.775 ;
     RECT  37.692 22.739 42.21 22.811 ;
     RECT  43.092 22.711 43.11 22.819 ;
     RECT  42.984 22.819 43.11 22.891 ;
     RECT  20.268 22.199 22.986 22.981 ;
     RECT  23.796 22.199 25.002 22.981 ;
     RECT  42.912 22.891 43.11 23.021 ;
     RECT  9.036 22.621 9.126 23.153 ;
     RECT  0.108 22.603 0.126 23.179 ;
     RECT  18.252 22.739 19.026 23.189 ;
     RECT  37.692 22.811 42.174 23.189 ;
     RECT  42.984 23.021 43.11 23.213 ;
     RECT  0.108 23.179 0.162 23.309 ;
     RECT  43.092 23.213 43.11 23.405 ;
     RECT  16.524 22.009 16.578 23.459 ;
     RECT  37.692 23.189 40.698 23.521 ;
     RECT  18.504 23.189 19.026 23.549 ;
     RECT  37.26 23.521 40.698 23.621 ;
     RECT  1.188 22.505 8.298 23.693 ;
     RECT  10.8 21.163 10.818 23.729 ;
     RECT  16.524 23.459 16.542 23.729 ;
     RECT  34.815 22.775 35.37 23.729 ;
     RECT  18.504 23.549 18.954 23.819 ;
     RECT  37.836 23.621 40.698 24.043 ;
     RECT  41.58 23.189 42.174 24.043 ;
     RECT  33.084 23.593 33.102 24.089 ;
     RECT  37.836 24.043 42.174 24.197 ;
     RECT  1.98 23.693 8.298 24.233 ;
     RECT  41.616 24.197 42.174 24.235 ;
     RECT  43.092 24.139 43.11 24.269 ;
     RECT  1.188 23.693 1.242 24.395 ;
     RECT  37.836 24.197 40.698 24.395 ;
     RECT  1.98 24.233 4.986 24.467 ;
     RECT  41.616 24.235 42.21 24.523 ;
     RECT  2.34 24.467 4.986 24.629 ;
     RECT  25.74 22.243 25.758 24.629 ;
     RECT  2.34 24.629 3.582 24.665 ;
     RECT  37.044 23.791 37.062 24.673 ;
     RECT  41.616 24.523 42.246 24.701 ;
     RECT  34.815 23.729 35.097 24.709 ;
     RECT  5.796 24.233 8.298 24.773 ;
     RECT  25.884 24.637 25.902 24.773 ;
     RECT  26.856 24.601 26.874 24.773 ;
     RECT  2.415 24.665 3.582 24.899 ;
     RECT  18.615 23.819 18.954 24.899 ;
     RECT  1.224 24.395 1.242 24.935 ;
     RECT  39.24 24.395 40.698 25.003 ;
     RECT  41.616 24.701 42.21 25.003 ;
     RECT  4.464 24.629 4.986 25.051 ;
     RECT  37.836 24.395 38.034 25.141 ;
     RECT  39.24 25.003 42.21 25.141 ;
     RECT  4.464 25.051 5.058 25.169 ;
     RECT  0.108 23.309 0.126 25.205 ;
     RECT  4.464 25.169 4.554 25.439 ;
     RECT  5.796 24.773 8.097 25.439 ;
     RECT  34.2 24.709 35.097 25.439 ;
     RECT  4.464 25.439 4.482 25.619 ;
     RECT  37.836 25.141 42.21 25.619 ;
     RECT  7.092 25.439 8.097 25.745 ;
     RECT  9.036 23.153 9.054 25.745 ;
     RECT  5.796 25.439 6.354 25.817 ;
     RECT  36.504 24.673 37.062 25.825 ;
     RECT  37.836 25.619 40.698 25.825 ;
     RECT  2.415 24.899 3.474 25.889 ;
     RECT  5.796 25.817 5.814 25.889 ;
     RECT  3.456 25.889 3.474 25.979 ;
     RECT  7.668 25.745 8.097 25.979 ;
     RECT  36.504 25.825 40.698 25.979 ;
     RECT  36.504 25.979 37.062 26.249 ;
     RECT  20.268 22.981 25.002 26.257 ;
     RECT  33.624 25.987 33.642 26.257 ;
     RECT  20.268 26.257 25.182 26.329 ;
     RECT  37.836 25.979 40.698 26.347 ;
     RECT  41.472 25.619 42.21 26.347 ;
     RECT  20.268 26.329 25.254 26.429 ;
     RECT  37.836 26.347 42.21 26.627 ;
     RECT  37.044 26.249 37.062 26.699 ;
     RECT  37.836 26.627 42.174 26.699 ;
     RECT  33.624 26.257 33.894 26.789 ;
     RECT  31.932 24.781 31.95 27.059 ;
     RECT  42.084 26.699 42.174 27.059 ;
     RECT  43.092 25.675 43.11 27.115 ;
     RECT  42.084 27.059 42.138 27.329 ;
     RECT  20.268 26.429 24.93 27.509 ;
     RECT  20.844 27.509 24.93 27.779 ;
     RECT  20.844 27.779 24.297 27.869 ;
     RECT  43.056 27.115 43.11 27.869 ;
     RECT  21.348 27.869 24.297 28.049 ;
     RECT  42.12 27.329 42.138 28.409 ;
     RECT  33.876 26.789 33.894 28.589 ;
     RECT  34.815 25.439 35.097 28.651 ;
     RECT  21.6 28.049 24.297 28.859 ;
     RECT  37.836 26.699 40.986 28.949 ;
     RECT  21.996 28.859 24.297 29.219 ;
     RECT  22.752 29.219 24.297 29.399 ;
     RECT  22.752 29.399 23.202 29.489 ;
     RECT  34.776 28.651 35.097 29.561 ;
     RECT  22.752 29.489 22.77 29.759 ;
     RECT  43.056 27.869 43.074 29.759 ;
     RECT  21.996 29.219 22.014 30.029 ;
     RECT  38.52 28.949 40.986 30.839 ;
     RECT  38.52 30.839 38.538 30.875 ;
     RECT  39.42 30.839 40.986 31.109 ;
     RECT  39.42 31.109 40.497 31.379 ;
     RECT  39.42 31.379 39.438 31.415 ;
     RECT  2.415 25.889 2.697 40.787 ;
     RECT  7.815 25.979 8.097 40.787 ;
     RECT  13.215 2.413 13.497 40.787 ;
     RECT  18.615 24.899 18.897 40.787 ;
     RECT  24.015 29.399 24.297 40.787 ;
     RECT  29.415 2.413 29.697 40.787 ;
     RECT  34.815 29.561 35.097 40.787 ;
     RECT  40.215 31.379 40.497 40.787 ;
     RECT  2.415 40.787 2.505 41.057 ;
     RECT  7.815 40.787 7.905 41.057 ;
     RECT  13.215 40.787 13.305 41.057 ;
     RECT  18.615 40.787 18.705 41.057 ;
     RECT  24.015 40.787 24.105 41.057 ;
     RECT  29.415 40.787 29.505 41.057 ;
     RECT  34.815 40.787 34.905 41.057 ;
     RECT  40.215 40.787 40.305 41.057 ;
    LAYER M4 ;
     RECT  0.06 15.792 0.133 23.208 ;
     RECT  0.133 15.792 0.137 23.304 ;
     RECT  0.137 15.888 0.173 23.304 ;
     RECT  0.173 15.984 2.408 23.304 ;
     RECT  2.408 2.148 2.512 41.052 ;
     RECT  2.512 2.418 2.704 40.782 ;
     RECT  2.704 15.984 2.765 16.68 ;
     RECT  2.704 17.712 2.873 23.304 ;
     RECT  2.873 17.712 3.089 21.48 ;
     RECT  2.873 23.28 3.089 23.304 ;
     RECT  3.089 17.712 3.125 17.736 ;
     RECT  3.089 19.584 3.125 21.48 ;
     RECT  3.125 19.584 3.161 21 ;
     RECT  3.161 20.976 3.197 21 ;
     RECT  3.161 19.584 3.377 19.848 ;
     RECT  2.765 16.656 3.449 16.68 ;
     RECT  3.377 19.584 4.417 19.608 ;
     RECT  4.417 18.672 4.489 19.608 ;
     RECT  4.453 22.752 4.601 22.776 ;
     RECT  3.913 17.136 4.849 17.16 ;
     RECT  4.777 15.936 4.981 15.96 ;
     RECT  4.849 17.136 4.981 17.688 ;
     RECT  4.381 21.696 5.029 21.72 ;
     RECT  4.705 23.232 5.101 23.256 ;
     RECT  4.981 15.936 5.177 17.688 ;
     RECT  4.489 18.672 5.177 20.328 ;
     RECT  5.029 21.6 5.221 21.72 ;
     RECT  5.177 15.936 5.465 15.96 ;
     RECT  5.177 19.584 5.717 20.328 ;
     RECT  5.101 23.232 5.753 23.784 ;
     RECT  5.221 21.456 6.289 21.72 ;
     RECT  5.717 19.584 6.329 20.04 ;
     RECT  5.177 17.664 6.361 17.688 ;
     RECT  5.753 23.232 6.401 23.256 ;
     RECT  6.361 17.568 6.469 17.688 ;
     RECT  6.289 21.456 6.649 21.768 ;
     RECT  6.469 17.568 6.685 18.456 ;
     RECT  6.329 19.584 6.685 19.896 ;
     RECT  6.649 21.456 6.757 22.248 ;
     RECT  6.757 21.072 6.973 22.248 ;
     RECT  6.973 21.072 7.381 22.488 ;
     RECT  6.829 16.56 7.808 16.584 ;
     RECT  6.685 17.568 7.808 19.896 ;
     RECT  7.381 20.976 7.808 22.488 ;
     RECT  7.808 2.148 7.912 41.052 ;
     RECT  7.912 2.418 8.104 40.782 ;
     RECT  8.104 16.272 8.237 16.392 ;
     RECT  8.237 16.272 8.345 16.296 ;
     RECT  13.208 2.148 13.312 41.052 ;
     RECT  13.312 2.418 13.504 40.782 ;
     RECT  18.608 2.148 18.712 41.052 ;
     RECT  18.712 2.418 18.904 40.782 ;
     RECT  24.008 2.148 24.112 41.052 ;
     RECT  24.112 2.418 24.304 40.782 ;
     RECT  29.408 2.148 29.512 41.052 ;
     RECT  29.512 2.418 29.704 40.782 ;
     RECT  34.808 2.148 34.912 41.052 ;
     RECT  34.912 2.418 35.104 40.782 ;
     RECT  39.913 26.64 39.949 26.664 ;
     RECT  39.949 26.304 39.985 26.808 ;
     RECT  39.985 25.488 40.208 26.808 ;
     RECT  40.208 2.148 40.312 41.052 ;
     RECT  40.312 2.418 40.504 40.782 ;
     RECT  40.504 19.92 43.045 27.048 ;
     RECT  43.045 19.92 43.164 27.144 ;
    LAYER M5 ;
     RECT  2.4 2.137 2.52 2.151 ;
     RECT  7.8 2.137 7.92 2.151 ;
     RECT  13.2 2.137 13.32 2.151 ;
     RECT  18.6 2.137 18.72 2.151 ;
     RECT  24 2.137 24.12 2.151 ;
     RECT  29.4 2.137 29.52 2.151 ;
     RECT  34.8 2.137 34.92 2.151 ;
     RECT  40.2 2.137 40.32 2.151 ;
     RECT  0.24 17.125 0.264 19.477 ;
     RECT  0.144 19.477 0.264 19.619 ;
     RECT  0.144 19.619 0.168 19.667 ;
     RECT  4.992 16.885 5.016 19.715 ;
     RECT  7.8 2.151 8.112 19.861 ;
     RECT  0.144 21.301 0.168 21.491 ;
     RECT  7.392 19.861 8.112 22.259 ;
     RECT  2.4 2.151 2.712 22.693 ;
     RECT  2.304 22.693 2.712 22.835 ;
     RECT  43.008 22.981 43.032 23.171 ;
     RECT  5.232 21.445 5.256 23.411 ;
     RECT  40.2 2.151 40.512 26.341 ;
     RECT  40.08 26.341 40.512 26.771 ;
     RECT  2.4 22.835 2.712 41.049 ;
     RECT  7.8 22.259 8.112 41.049 ;
     RECT  13.2 2.151 13.512 41.049 ;
     RECT  18.6 2.151 18.912 41.049 ;
     RECT  24 2.151 24.312 41.049 ;
     RECT  29.4 2.151 29.712 41.049 ;
     RECT  34.8 2.151 35.112 41.049 ;
     RECT  40.2 26.771 40.512 41.049 ;
     RECT  2.4 41.049 2.52 41.063 ;
     RECT  7.8 41.049 7.92 41.063 ;
     RECT  13.2 41.049 13.32 41.063 ;
     RECT  18.6 41.049 18.72 41.063 ;
     RECT  24 41.049 24.12 41.063 ;
     RECT  29.4 41.049 29.52 41.063 ;
     RECT  34.8 41.049 34.92 41.063 ;
     RECT  40.2 41.049 40.32 41.063 ;
  END
END ot_hgi_sm_pub_cmd_relay
END LIBRARY
